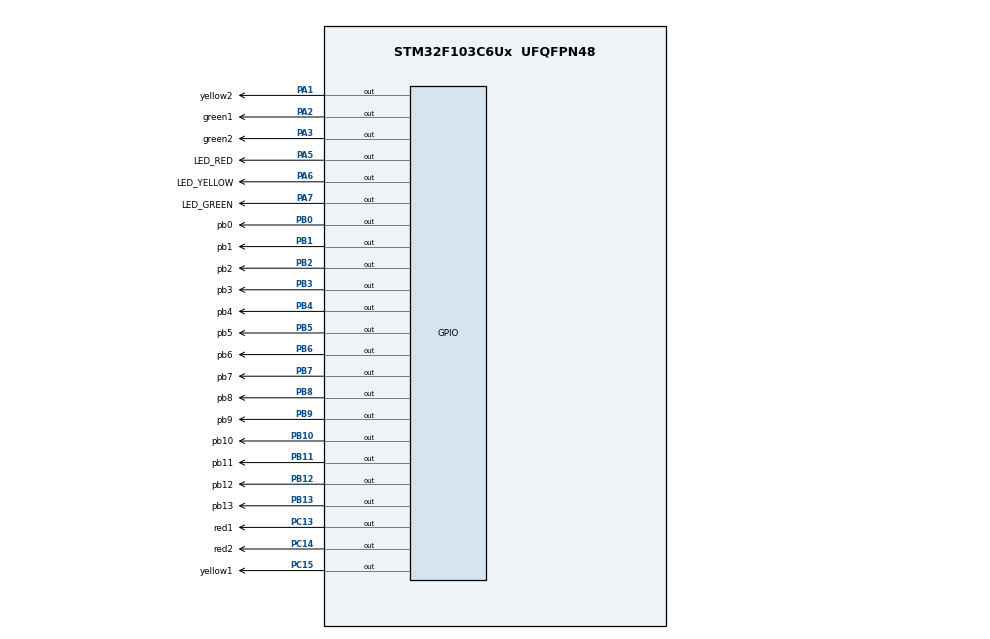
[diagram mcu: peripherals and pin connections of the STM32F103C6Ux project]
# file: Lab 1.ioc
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Mcu.Family=STM32F1
Mcu.Name=STM32F103C6Ux
Mcu.Package=UFQFPN48
NVIC.PriorityGroup=NVIC_PRIORITYGROUP_4
PA1.GPIO_Label=yellow2
PA1.Signal=GPIO_Output
PA2.GPIO_Label=green1
PA2.Signal=GPIO_Output
PA3.GPIO_Label=green2
PA3.Signal=GPIO_Output
PA5.GPIO_Label=LED_RED
PA5.Signal=GPIO_Output
PA6.GPIO_Label=LED_YELLOW
PA6.Signal=GPIO_Output
PA7.GPIO_Label=LED_GREEN
PA7.Signal=GPIO_Output
PB0.GPIO_Label=pb0
PB0.Signal=GPIO_Output
PB1.GPIO_Label=pb1
PB1.Signal=GPIO_Output
PB10.GPIO_Label=pb10
PB10.Signal=GPIO_Output
PB11.GPIO_Label=pb11
PB11.Signal=GPIO_Output
PB12.GPIO_Label=pb12
PB12.Signal=GPIO_Output
PB13.GPIO_Label=pb13
PB13.Signal=GPIO_Output
PB2.GPIO_Label=pb2
PB2.Signal=GPIO_Output
PB3.GPIO_Label=pb3
PB3.Signal=GPIO_Output
PB4.GPIO_Label=pb4
PB4.Signal=GPIO_Output
PB5.GPIO_Label=pb5
PB5.Signal=GPIO_Output
PB6.GPIO_Label=pb6
PB6.Signal=GPIO_Output
PB7.GPIO_Label=pb7
PB7.Signal=GPIO_Output
PB8.GPIO_Label=pb8
PB8.Signal=GPIO_Output
PB9.GPIO_Label=pb9
PB9.Signal=GPIO_Output
PC13-TAMPER-RTC.GPIO_Label=red1
PC13-TAMPER-RTC.Signal=GPIO_Output
PC14-OSC32_IN.GPIO_Label=red2
PC14-OSC32_IN.Signal=GPIO_Output
PC15-OSC32_OUT.GPIO_Label=yellow1
PC15-OSC32_OUT.Signal=GPIO_Output
ProjectManager.HeapSize=0x200
ProjectManager.StackSize=0x400
ProjectManager.TargetToolchain=STM32CubeIDE
RCC.APB1Freq_Value=8000000
RCC.APB2Freq_Value=8000000
VP_SYS_VS_ND.Mode=No_Debug
board=custom

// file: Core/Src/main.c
/* USER CODE BEGIN Header */
/**
  ******************************************************************************
  * @file           : main.c
  * @brief          : Main program body
  ******************************************************************************
  * @attention
  *
  * <h2><center>&copy; Copyright (c) 2024 STMicroelectronics.
  * All rights reserved.</center></h2>
  *
  * This software component is licensed by ST under BSD 3-Clause license,
  * the "License"; You may not use this file except in compliance with the
  * License. You may obtain a copy of the License at:
  *                        opensource.org/licenses/BSD-3-Clause
  *
  ******************************************************************************
  */
/* USER CODE END Header */
#include "main.h"

/* USER CODE BEGIN Includes */
#include "Exercise 678910.h"

/* USER CODE END Includes */

void SystemClock_Config(void);
static void MX_GPIO_Init(void);

int main(void)
{
  /* USER CODE BEGIN 1 */
	init_exercise678910();
  /* USER CODE END 1 */

  /* MCU Configuration--------------------------------------------------------*/

  /* Reset of all peripherals, Initializes the Flash interface and the Systick. */
  HAL_Init();

  /* Configure the system clock */
  SystemClock_Config();

  /* Initialize all configured peripherals */
  MX_GPIO_Init();

  /* Infinite loop */
  /* USER CODE BEGIN WHILE */
  while (1)
  {
	  //run_exercise6();
//	  run_exercise7();
//	  run_exercise8();
//	  run_exercise9();
	  run_exercise10();
	  HAL_Delay(10);
	  //clearAllClock();
    /* USER CODE END WHILE */

  }
}

void SystemClock_Config(void)
{
  RCC_OscInitTypeDef RCC_OscInitStruct = {0};
  RCC_ClkInitTypeDef RCC_ClkInitStruct = {0};

  /** Initializes the RCC Oscillators according to the specified parameters
  * in the RCC_OscInitTypeDef structure.
  */
  RCC_OscInitStruct.OscillatorType = RCC_OSCILLATORTYPE_HSI;
  RCC_OscInitStruct.HSIState = RCC_HSI_ON;
  RCC_OscInitStruct.HSICalibrationValue = RCC_HSICALIBRATION_DEFAULT;
  RCC_OscInitStruct.PLL.PLLState = RCC_PLL_NONE;
  if (HAL_RCC_OscConfig(&RCC_OscInitStruct) != HAL_OK)
  {
    Error_Handler();
  }
  /** Initializes the CPU, AHB and APB buses clocks
  */
  RCC_ClkInitStruct.ClockType = RCC_CLOCKTYPE_HCLK|RCC_CLOCKTYPE_SYSCLK
                              |RCC_CLOCKTYPE_PCLK1|RCC_CLOCKTYPE_PCLK2;
  RCC_ClkInitStruct.SYSCLKSource = RCC_SYSCLKSOURCE_HSI;
  RCC_ClkInitStruct.AHBCLKDivider = RCC_SYSCLK_DIV1;
  RCC_ClkInitStruct.APB1CLKDivider = RCC_HCLK_DIV1;
  RCC_ClkInitStruct.APB2CLKDivider = RCC_HCLK_DIV1;

  if (HAL_RCC_ClockConfig(&RCC_ClkInitStruct, FLASH_LATENCY_0) != HAL_OK)
  {
    Error_Handler();
  }
}

static void MX_GPIO_Init(void)
{
  GPIO_InitTypeDef GPIO_InitStruct = {0};

  /* GPIO Ports Clock Enable */
  __HAL_RCC_GPIOC_CLK_ENABLE();
  __HAL_RCC_GPIOA_CLK_ENABLE();
  __HAL_RCC_GPIOB_CLK_ENABLE();

  /*Configure GPIO pin Output Level */
  HAL_GPIO_WritePin(GPIOC, red1_Pin|red2_Pin|yellow1_Pin, GPIO_PIN_RESET);

  /*Configure GPIO pin Output Level */
  HAL_GPIO_WritePin(GPIOA, yellow2_Pin|green1_Pin|green2_Pin|pa4_Pin
                          |pa5_Pin|pa6_Pin|pa7_Pin|pa8_Pin
                          |pa9_Pin|pa10_Pin|pa11_Pin|pa12_Pin
                          |pa13_Pin|pa14_Pin|pa15_Pin, GPIO_PIN_RESET);

  /*Configure GPIO pin Output Level */
  HAL_GPIO_WritePin(GPIOB, pb0_Pin|pb1_Pin|pb2_Pin|pb3_Pin
                          |pb4_Pin|pb5_Pin|pb6_Pin, GPIO_PIN_RESET);

  /*Configure GPIO pins : red1_Pin red2_Pin yellow1_Pin */
  GPIO_InitStruct.Pin = red1_Pin|red2_Pin|yellow1_Pin;
  GPIO_InitStruct.Mode = GPIO_MODE_OUTPUT_PP;
  GPIO_InitStruct.Pull = GPIO_NOPULL;
  GPIO_InitStruct.Speed = GPIO_SPEED_FREQ_LOW;
  HAL_GPIO_Init(GPIOC, &GPIO_InitStruct);

  /*Configure GPIO pins : yellow2_Pin green1_Pin green2_Pin pa4_Pin
                           pa5_Pin pa6_Pin pa7_Pin pa8_Pin
                           pa9_Pin pa10_Pin pa11_Pin pa12_Pin
                           pa13_Pin pa14_Pin pa15_Pin */
  GPIO_InitStruct.Pin = yellow2_Pin|green1_Pin|green2_Pin|pa4_Pin
                          |pa5_Pin|pa6_Pin|pa7_Pin|pa8_Pin
                          |pa9_Pin|pa10_Pin|pa11_Pin|pa12_Pin
                          |pa13_Pin|pa14_Pin|pa15_Pin;
  GPIO_InitStruct.Mode = GPIO_MODE_OUTPUT_PP;
  GPIO_InitStruct.Pull = GPIO_NOPULL;
  GPIO_InitStruct.Speed = GPIO_SPEED_FREQ_LOW;
  HAL_GPIO_Init(GPIOA, &GPIO_InitStruct);

  /*Configure GPIO pins : pb0_Pin pb1_Pin pb2_Pin pb3_Pin
                           pb4_Pin pb5_Pin pb6_Pin */
  GPIO_InitStruct.Pin = pb0_Pin|pb1_Pin|pb2_Pin|pb3_Pin
                          |pb4_Pin|pb5_Pin|pb6_Pin;
  GPIO_InitStruct.Mode = GPIO_MODE_OUTPUT_PP;
  GPIO_InitStruct.Pull = GPIO_NOPULL;
  GPIO_InitStruct.Speed = GPIO_SPEED_FREQ_LOW;
  HAL_GPIO_Init(GPIOB, &GPIO_InitStruct);

}

void Error_Handler(void)
{
  __disable_irq();
  while (1)
  {
  }
}

/************************ (C) COPYRIGHT STMicroelectronics *****END OF FILE****/
